# Generated by innovus_enablement/scripts/gen_fakeram.py: abstract 64x15 SRAM.
# Geometry is an assumption (see script header), not PDK data.
VERSION 5.8 ;
BUSBITCHARS "[]" ;
DIVIDERCHAR "/" ;

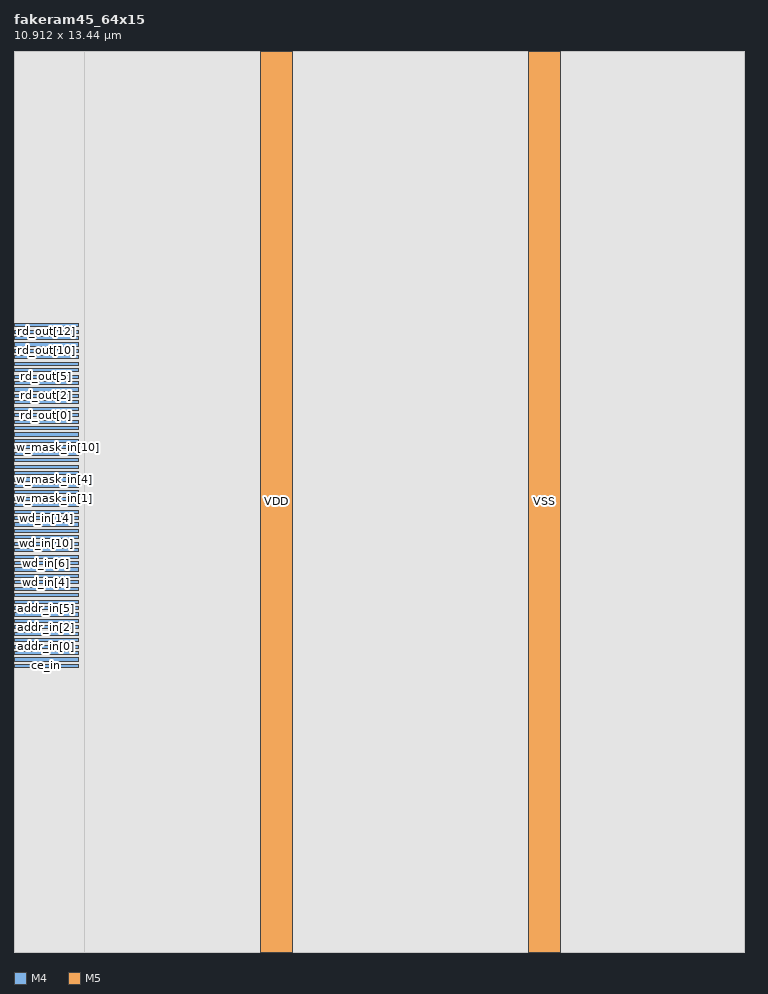
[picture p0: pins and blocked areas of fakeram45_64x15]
MACRO fakeram45_64x15
  CLASS BLOCK ;
  FOREIGN fakeram45_64x15 0 0 ;
  ORIGIN 0 0 ;
  SIZE 10.9120 BY 13.4400 ;
  SYMMETRY X Y R90 ;
  PIN clk
    DIRECTION INPUT ;
    USE CLOCK ;
    PORT
      LAYER M4 ;
        RECT 0 4.2480 0.9600 4.2960 ;
    END
  END clk
  PIN ce_in
    DIRECTION INPUT ;
    USE SIGNAL ;
    PORT
      LAYER M4 ;
        RECT 0 4.3440 0.9600 4.3920 ;
    END
  END ce_in
  PIN we_in
    DIRECTION INPUT ;
    USE SIGNAL ;
    PORT
      LAYER M4 ;
        RECT 0 4.4400 0.9600 4.4880 ;
    END
  END we_in
  PIN addr_in[0]
    DIRECTION INPUT ;
    USE SIGNAL ;
    PORT
      LAYER M4 ;
        RECT 0 4.5360 0.9600 4.5840 ;
    END
  END addr_in[0]
  PIN addr_in[1]
    DIRECTION INPUT ;
    USE SIGNAL ;
    PORT
      LAYER M4 ;
        RECT 0 4.6320 0.9600 4.6800 ;
    END
  END addr_in[1]
  PIN addr_in[2]
    DIRECTION INPUT ;
    USE SIGNAL ;
    PORT
      LAYER M4 ;
        RECT 0 4.7280 0.9600 4.7760 ;
    END
  END addr_in[2]
  PIN addr_in[3]
    DIRECTION INPUT ;
    USE SIGNAL ;
    PORT
      LAYER M4 ;
        RECT 0 4.8240 0.9600 4.8720 ;
    END
  END addr_in[3]
  PIN addr_in[4]
    DIRECTION INPUT ;
    USE SIGNAL ;
    PORT
      LAYER M4 ;
        RECT 0 4.9200 0.9600 4.9680 ;
    END
  END addr_in[4]
  PIN addr_in[5]
    DIRECTION INPUT ;
    USE SIGNAL ;
    PORT
      LAYER M4 ;
        RECT 0 5.0160 0.9600 5.0640 ;
    END
  END addr_in[5]
  PIN wd_in[0]
    DIRECTION INPUT ;
    USE SIGNAL ;
    PORT
      LAYER M4 ;
        RECT 0 5.1120 0.9600 5.1600 ;
    END
  END wd_in[0]
  PIN wd_in[1]
    DIRECTION INPUT ;
    USE SIGNAL ;
    PORT
      LAYER M4 ;
        RECT 0 5.2080 0.9600 5.2560 ;
    END
  END wd_in[1]
  PIN wd_in[2]
    DIRECTION INPUT ;
    USE SIGNAL ;
    PORT
      LAYER M4 ;
        RECT 0 5.3040 0.9600 5.3520 ;
    END
  END wd_in[2]
  PIN wd_in[3]
    DIRECTION INPUT ;
    USE SIGNAL ;
    PORT
      LAYER M4 ;
        RECT 0 5.4000 0.9600 5.4480 ;
    END
  END wd_in[3]
  PIN wd_in[4]
    DIRECTION INPUT ;
    USE SIGNAL ;
    PORT
      LAYER M4 ;
        RECT 0 5.4960 0.9600 5.5440 ;
    END
  END wd_in[4]
  PIN wd_in[5]
    DIRECTION INPUT ;
    USE SIGNAL ;
    PORT
      LAYER M4 ;
        RECT 0 5.5920 0.9600 5.6400 ;
    END
  END wd_in[5]
  PIN wd_in[6]
    DIRECTION INPUT ;
    USE SIGNAL ;
    PORT
      LAYER M4 ;
        RECT 0 5.6880 0.9600 5.7360 ;
    END
  END wd_in[6]
  PIN wd_in[7]
    DIRECTION INPUT ;
    USE SIGNAL ;
    PORT
      LAYER M4 ;
        RECT 0 5.7840 0.9600 5.8320 ;
    END
  END wd_in[7]
  PIN wd_in[8]
    DIRECTION INPUT ;
    USE SIGNAL ;
    PORT
      LAYER M4 ;
        RECT 0 5.8800 0.9600 5.9280 ;
    END
  END wd_in[8]
  PIN wd_in[9]
    DIRECTION INPUT ;
    USE SIGNAL ;
    PORT
      LAYER M4 ;
        RECT 0 5.9760 0.9600 6.0240 ;
    END
  END wd_in[9]
  PIN wd_in[10]
    DIRECTION INPUT ;
    USE SIGNAL ;
    PORT
      LAYER M4 ;
        RECT 0 6.0720 0.9600 6.1200 ;
    END
  END wd_in[10]
  PIN wd_in[11]
    DIRECTION INPUT ;
    USE SIGNAL ;
    PORT
      LAYER M4 ;
        RECT 0 6.1680 0.9600 6.2160 ;
    END
  END wd_in[11]
  PIN wd_in[12]
    DIRECTION INPUT ;
    USE SIGNAL ;
    PORT
      LAYER M4 ;
        RECT 0 6.2640 0.9600 6.3120 ;
    END
  END wd_in[12]
  PIN wd_in[13]
    DIRECTION INPUT ;
    USE SIGNAL ;
    PORT
      LAYER M4 ;
        RECT 0 6.3600 0.9600 6.4080 ;
    END
  END wd_in[13]
  PIN wd_in[14]
    DIRECTION INPUT ;
    USE SIGNAL ;
    PORT
      LAYER M4 ;
        RECT 0 6.4560 0.9600 6.5040 ;
    END
  END wd_in[14]
  PIN w_mask_in[0]
    DIRECTION INPUT ;
    USE SIGNAL ;
    PORT
      LAYER M4 ;
        RECT 0 6.5520 0.9600 6.6000 ;
    END
  END w_mask_in[0]
  PIN w_mask_in[1]
    DIRECTION INPUT ;
    USE SIGNAL ;
    PORT
      LAYER M4 ;
        RECT 0 6.6480 0.9600 6.6960 ;
    END
  END w_mask_in[1]
  PIN w_mask_in[2]
    DIRECTION INPUT ;
    USE SIGNAL ;
    PORT
      LAYER M4 ;
        RECT 0 6.7440 0.9600 6.7920 ;
    END
  END w_mask_in[2]
  PIN w_mask_in[3]
    DIRECTION INPUT ;
    USE SIGNAL ;
    PORT
      LAYER M4 ;
        RECT 0 6.8400 0.9600 6.8880 ;
    END
  END w_mask_in[3]
  PIN w_mask_in[4]
    DIRECTION INPUT ;
    USE SIGNAL ;
    PORT
      LAYER M4 ;
        RECT 0 6.9360 0.9600 6.9840 ;
    END
  END w_mask_in[4]
  PIN w_mask_in[5]
    DIRECTION INPUT ;
    USE SIGNAL ;
    PORT
      LAYER M4 ;
        RECT 0 7.0320 0.9600 7.0800 ;
    END
  END w_mask_in[5]
  PIN w_mask_in[6]
    DIRECTION INPUT ;
    USE SIGNAL ;
    PORT
      LAYER M4 ;
        RECT 0 7.1280 0.9600 7.1760 ;
    END
  END w_mask_in[6]
  PIN w_mask_in[7]
    DIRECTION INPUT ;
    USE SIGNAL ;
    PORT
      LAYER M4 ;
        RECT 0 7.2240 0.9600 7.2720 ;
    END
  END w_mask_in[7]
  PIN w_mask_in[8]
    DIRECTION INPUT ;
    USE SIGNAL ;
    PORT
      LAYER M4 ;
        RECT 0 7.3200 0.9600 7.3680 ;
    END
  END w_mask_in[8]
  PIN w_mask_in[9]
    DIRECTION INPUT ;
    USE SIGNAL ;
    PORT
      LAYER M4 ;
        RECT 0 7.4160 0.9600 7.4640 ;
    END
  END w_mask_in[9]
  PIN w_mask_in[10]
    DIRECTION INPUT ;
    USE SIGNAL ;
    PORT
      LAYER M4 ;
        RECT 0 7.5120 0.9600 7.5600 ;
    END
  END w_mask_in[10]
  PIN w_mask_in[11]
    DIRECTION INPUT ;
    USE SIGNAL ;
    PORT
      LAYER M4 ;
        RECT 0 7.6080 0.9600 7.6560 ;
    END
  END w_mask_in[11]
  PIN w_mask_in[12]
    DIRECTION INPUT ;
    USE SIGNAL ;
    PORT
      LAYER M4 ;
        RECT 0 7.7040 0.9600 7.7520 ;
    END
  END w_mask_in[12]
  PIN w_mask_in[13]
    DIRECTION INPUT ;
    USE SIGNAL ;
    PORT
      LAYER M4 ;
        RECT 0 7.8000 0.9600 7.8480 ;
    END
  END w_mask_in[13]
  PIN w_mask_in[14]
    DIRECTION INPUT ;
    USE SIGNAL ;
    PORT
      LAYER M4 ;
        RECT 0 7.8960 0.9600 7.9440 ;
    END
  END w_mask_in[14]
  PIN rd_out[0]
    DIRECTION OUTPUT ;
    USE SIGNAL ;
    PORT
      LAYER M4 ;
        RECT 0 7.9920 0.9600 8.0400 ;
    END
  END rd_out[0]
  PIN rd_out[1]
    DIRECTION OUTPUT ;
    USE SIGNAL ;
    PORT
      LAYER M4 ;
        RECT 0 8.0880 0.9600 8.1360 ;
    END
  END rd_out[1]
  PIN rd_out[2]
    DIRECTION OUTPUT ;
    USE SIGNAL ;
    PORT
      LAYER M4 ;
        RECT 0 8.1840 0.9600 8.2320 ;
    END
  END rd_out[2]
  PIN rd_out[3]
    DIRECTION OUTPUT ;
    USE SIGNAL ;
    PORT
      LAYER M4 ;
        RECT 0 8.2800 0.9600 8.3280 ;
    END
  END rd_out[3]
  PIN rd_out[4]
    DIRECTION OUTPUT ;
    USE SIGNAL ;
    PORT
      LAYER M4 ;
        RECT 0 8.3760 0.9600 8.4240 ;
    END
  END rd_out[4]
  PIN rd_out[5]
    DIRECTION OUTPUT ;
    USE SIGNAL ;
    PORT
      LAYER M4 ;
        RECT 0 8.4720 0.9600 8.5200 ;
    END
  END rd_out[5]
  PIN rd_out[6]
    DIRECTION OUTPUT ;
    USE SIGNAL ;
    PORT
      LAYER M4 ;
        RECT 0 8.5680 0.9600 8.6160 ;
    END
  END rd_out[6]
  PIN rd_out[7]
    DIRECTION OUTPUT ;
    USE SIGNAL ;
    PORT
      LAYER M4 ;
        RECT 0 8.6640 0.9600 8.7120 ;
    END
  END rd_out[7]
  PIN rd_out[8]
    DIRECTION OUTPUT ;
    USE SIGNAL ;
    PORT
      LAYER M4 ;
        RECT 0 8.7600 0.9600 8.8080 ;
    END
  END rd_out[8]
  PIN rd_out[9]
    DIRECTION OUTPUT ;
    USE SIGNAL ;
    PORT
      LAYER M4 ;
        RECT 0 8.8560 0.9600 8.9040 ;
    END
  END rd_out[9]
  PIN rd_out[10]
    DIRECTION OUTPUT ;
    USE SIGNAL ;
    PORT
      LAYER M4 ;
        RECT 0 8.9520 0.9600 9.0000 ;
    END
  END rd_out[10]
  PIN rd_out[11]
    DIRECTION OUTPUT ;
    USE SIGNAL ;
    PORT
      LAYER M4 ;
        RECT 0 9.0480 0.9600 9.0960 ;
    END
  END rd_out[11]
  PIN rd_out[12]
    DIRECTION OUTPUT ;
    USE SIGNAL ;
    PORT
      LAYER M4 ;
        RECT 0 9.1440 0.9600 9.1920 ;
    END
  END rd_out[12]
  PIN rd_out[13]
    DIRECTION OUTPUT ;
    USE SIGNAL ;
    PORT
      LAYER M4 ;
        RECT 0 9.2400 0.9600 9.2880 ;
    END
  END rd_out[13]
  PIN rd_out[14]
    DIRECTION OUTPUT ;
    USE SIGNAL ;
    PORT
      LAYER M4 ;
        RECT 0 9.3360 0.9600 9.3840 ;
    END
  END rd_out[14]
  PIN VDD
    DIRECTION INOUT ;
    USE POWER ;
    PORT
      LAYER M5 ;
        RECT 3.6800 0 4.1600 13.4400 ;
    END
  END VDD
  PIN VSS
    DIRECTION INOUT ;
    USE GROUND ;
    PORT
      LAYER M5 ;
        RECT 7.6800 0 8.1600 13.4400 ;
    END
  END VSS
  OBS
    LAYER M0 ;
      RECT 0 0 10.9120 13.4400 ;
    LAYER M1 ;
      RECT 0 0 10.9120 13.4400 ;
    LAYER M2 ;
      RECT 0 0 10.9120 13.4400 ;
    LAYER M3 ;
      RECT 0 0 10.9120 13.4400 ;
    LAYER VIA0 ;
      RECT 0 0 10.9120 13.4400 ;
    LAYER VIA1 ;
      RECT 0 0 10.9120 13.4400 ;
    LAYER VIA2 ;
      RECT 0 0 10.9120 13.4400 ;
    LAYER VIA3 ;
      RECT 0 0 10.9120 13.4400 ;
    LAYER M4 ;
      RECT 1.0560 0 10.9120 13.4400 ;
  END
END fakeram45_64x15

END LIBRARY
